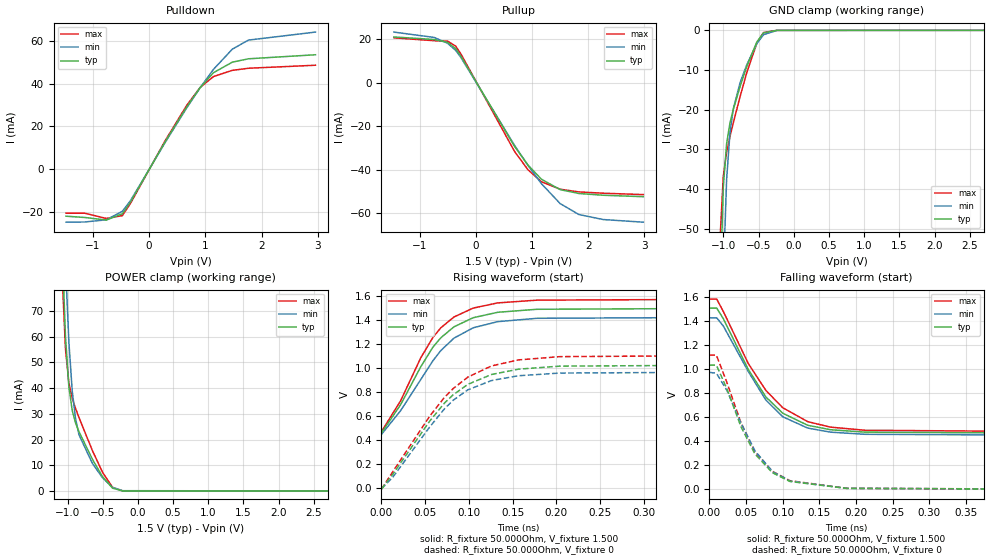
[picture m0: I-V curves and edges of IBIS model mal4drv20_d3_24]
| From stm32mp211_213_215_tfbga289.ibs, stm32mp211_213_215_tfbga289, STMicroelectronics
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[Model] mal4drv20_d3_24
Model_type   I/O
Polarity   Non-Inverting
Enable   Active-High
C_comp   1.836pF   1.830pF   1.844pF
C_comp_pullup   929.639fF   923.197fF   937.397fF
C_comp_pulldown 781.611fF   776.676fF   790.636fF
Vinh = 885.000mV
Vinl = 615.000mV
Vmeas = 750.000mV
Vref = 750.000mV
Rref = 50Ohms
Cref = 0pF
[Model Spec]
Vinh   885.000mV   848.000mV   923.000mV
Vinl   615.000mV   578.000mV   653.000mV
Vmeas   750.000mV   713.000mV   788.000mV
Vref   750.000mV   713.000mV   788.000mV
D_overshoot_ampl_h 0.4 NA   NA
D_overshoot_ampl_l 0.4 NA   NA
D_overshoot_area_l 100.000m NA   NA
D_overshoot_area_h 100.000m NA   NA
[Receiver Thresholds]
Vth = 750.000mV
Vth_min = 713.000mV
Vth_max = 788.000mV
Vinh_ac = 135.000mV
Vinh_dc = 100.000mV
Vinl_ac = -135.000mV
Vinl_dc = -100.000mV
Tslew_ac = 5.000ns
Threshold_sensitivity = 0.5
Reference_supply Pullup_ref
[Temperature Range]   25.000   125.000   -40.000
[Voltage Range]   1.500V   1.425V   1.575V
[GND Clamp Reference]   0.00V   0.00V   0.00V
[C Comp Corner]
| variable   typ   min   max
C_comp 1.844pF   1.836pF   1.830pF
C_comp_pullup 929.639fF   937.397fF   923.197fF
C_comp_pulldown 776.676fF   790.636fF   781.611fF
[Pulldown Reference]   0.00V   0.00V   0.00V
[POWER Clamp Reference]   1.500V   1.425V   1.575V
[Pullup Reference]   1.500V   1.425V   1.575V
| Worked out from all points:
|   slope of the pulldown table from 0 to 0.225 V, typ, clamps not added: 22.1 ohm
|   slope of the pullup table from 0 to 0.225 V, typ, clamps not added: 22.5 ohm
|   GND clamp passes 1 mA (typ) near -0.45 V on its own axis
|   POWER clamp passes 1 mA (typ) near -0.36 V on its own axis
|   rising waveform, R_fixture 50.000Ohm, V_fixture 1.500: 20-80 % time 54ps typ, 57.9ps min, 51.5ps max; typ from 0.461 V to 1.5 V
|   rising waveform, R_fixture 50.000Ohm, V_fixture 0: 20-80 % time 69.1ps typ, 66.6ps min, 71.4ps max; typ from -0.006 V to 1.03 V
|   falling waveform, R_fixture 50.000Ohm, V_fixture 1.500: 20-80 % time 62.2ps typ, 60.1ps min, 67.5ps max; typ from 1.51 V to 0.465 V
|   falling waveform, R_fixture 50.000Ohm, V_fixture 0: 20-80 % time 48.8ps typ, 50.1ps min, 49.4ps max; typ from 1.03 V to 0 V
[GND Clamp]
-1.48V    -1.637A    -1.644A    -1.658A
-1.05V    -67.86mA   -111.2mA   -53.06mA
-1.002V   -39.45mA   -62.21mA   -36.77mA
-954.6mV  -28.48mA   -37.5mA    -30.67mA
-906.8mV  -23.32mA   -25.75mA   -26.73mA
-859.1mV  -19.86mA   -19.72mA   -23.25mA
-763.6mV  -14.17mA   -13.2mA    -16.7mA
-668.2mV  -9.09mA    -8.668mA   -10.65mA
-525mV    -2.932mA   -3.341mA   -3.236mA
-429.5mV  -625.7uA   -1.091mA   -535.7uA
-238.6mV  -2.309uA   -20.7uA    -473nA
2.959V    72.19nA    968.6nA    105nA
[Power Clamp]
-1.459V   654.6mA    675.2mA    655.4mA
-1.077V   94.79mA    129.9mA    83.6mA
-1.03V    59.92mA    88.13mA    55.16mA
-981.8mV  40.46mA    57.96mA    42.01mA
-934.1mV  31.26mA    38.88mA    36.03mA
-886.4mV  26.43mA    28.01mA    32.07mA
-838.6mV  23.06mA    21.89mA    28.58mA
-647.7mV  12.32mA    10.7mA     15.7mA
-504.6mV  5.603mA    5.163mA    7.311mA
-361.4mV  1.062mA    1.366mA    1.412mA
-218.2mV  16.86uA    87.94uA    13.19uA
2.98V     -71.2nA    -1.524uA   -71.42nA
[Pulldown]
-1.48V    -22mA      -24.8mA    -20.6mA
-1.145V   -22.6mA    -24.7mA    -20.6mA
-763.6mV  -23.8mA    -23.7mA    -23.05mA
-477.3mV  -20.88mA   -19.72mA   -21.75mA
-334.1mV  -15.42mA   -14.8mA    -16.09mA
286.4mV   12.91mA    12.56mA    13.39mA
668.2mV   29.09mA    28.64mA    29.82mA
906.8mV   38.09mA    38.07mA    38.2mA
1.145V    45.13mA    46.69mA    43.32mA
1.48V     50.04mA    56.12mA    46.2mA
1.766V    51.61mA    60.36mA    47.19mA
2.959V    53.5mA     64.1mA     48.6mA
[Pullup]
-1.459V   20.9mA     23.14mA    20.5mA
-743.2mV  19.74mA    20.69mA    19.18mA
-504.6mV  18.41mA    18.01mA    18.98mA
-361.4mV  15.58mA    14.78mA    16.73mA
-265.9mV  12mA       11.46mA    13.06mA
688.6mV   -29.34mA   -28.88mA   -31.66mA
927.3mV   -37.9mA    -38.06mA   -40.07mA
1.166V    -44.38mA   -46.42mA   -45.55mA
1.5V      -49.17mA   -55.59mA   -48.97mA
1.834V    -50.94mA   -60.59mA   -50.21mA
2.264V    -51.73mA   -62.88mA   -50.8mA
2.98V     -52.4mA    -64.1mA    -51.44mA
[Ramp]
R_load=50.000Ohm
dV/dt_r   618.870mV/62.500ps  583.738mV/63.000ps  661.260mV/62.500ps
dV/dt_f   618.870mV/56.500ps  583.739mV/56.000ps  661.260mV/59.500ps
[Rising waveform]
R_fixture=50.000Ohm
V_fixture=1.500
V_fixture_min=1.425
V_fixture_max=1.575
0s        461.2mV    448.8mV    471.8mV
22ps      697.2mV    647.1mV    729.7mV
45ps      1.012V     905.9mV    1.086V
59ps      1.176V     1.063V     1.257V
68ps      1.253V     1.147V     1.336V
83ps      1.344V     1.25V      1.426V
105ps     1.42V      1.336V     1.5V
133ps     1.465V     1.387V     1.543V
178ps     1.49V      1.415V     1.566V
469ps     1.5V       1.425V     1.575V
[Rising waveform]
R_fixture=50.000Ohm
V_fixture=0
0s        -6.259mV   -3.866mV   -6.386mV
13ps      118mV      92.93mV    139mV
55ps      557.6mV    508.8mV    598.4mV
72ps      708.9mV    661.2mV    756.2mV
82ps      778.3mV    733.1mV    830mV
99ps      865.9mV    820.4mV    926.4mV
126ps     947.6mV    897.3mV    1.019V
157ps     992mV      937.3mV    1.069V
204ps     1.017V     959.4mV    1.096V
469ps     1.028V     969.6mV    1.108V
[Falling waveform]
R_fixture=50.000Ohm
V_fixture=1.500
V_fixture_min=1.425
V_fixture_max=1.575
0s        1.507V     1.426V     1.582V
10ps      1.507V     1.426V     1.582V
19ps      1.419V     1.358V     1.479V
53ps      996.3mV    980mV      1.046V
77ps      767.4mV    741.6mV    822.1mV
100ps     632.1mV    602.5mV    677.9mV
134ps     531.8mV    508.5mV    562mV
165ps     494.7mV    474.5mV    516.3mV
212ps     474.5mV    456.6mV    490.3mV
479ps     465.4mV    448.9mV    478.4mV
[Falling waveform]
R_fixture=50.000Ohm
V_fixture=0
0s        1.032V     971.6mV    1.116V
9ps       1.032V     965.5mV    1.116V
11ps      1.013V     951.5mV    1.093V
24ps      834.2mV    820.4mV    886.5mV
43ps      521.2mV    551.5mV    553.3mV
62ps      293.7mV    320.4mV    313.5mV
86ps      136.3mV    146.4mV    148.1mV
110ps     63.83mV    68.15mV    70.31mV
187ps     6.519mV    6.582mV    7.409mV
478ps     3.689uV    11.19uV    3.754uV
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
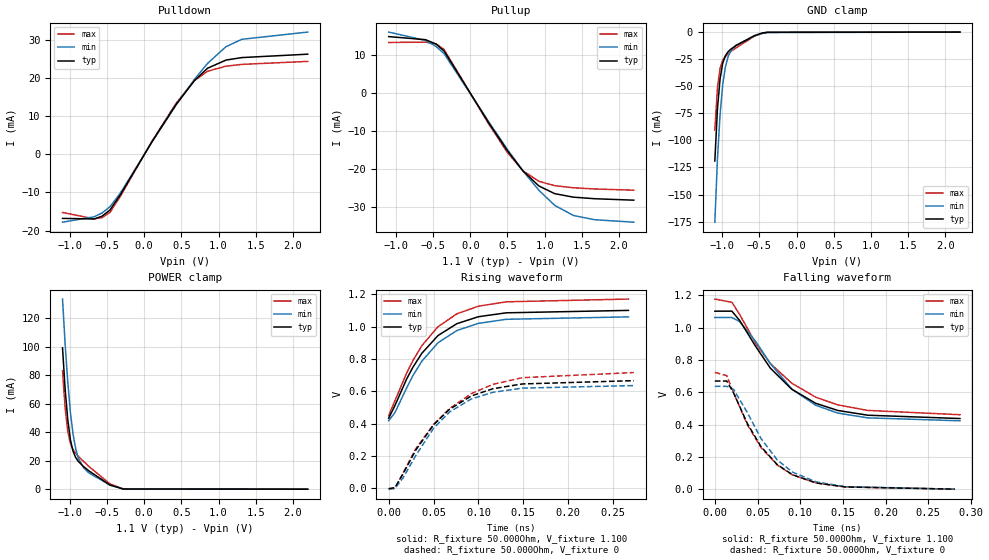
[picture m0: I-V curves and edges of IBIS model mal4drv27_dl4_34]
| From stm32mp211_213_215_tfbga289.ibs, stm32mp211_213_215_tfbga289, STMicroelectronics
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[Model] mal4drv27_dl4_34
Model_type   I/O
Polarity   Non-Inverting
Enable   Active-High
C_comp   1.656pF   1.654pF   1.662pF
C_comp_pullup   832.475fF   825.290fF   839.619fF
C_comp_pulldown 737.556fF   736.745fF   750.731fF
Vinh = 387.000mV
Vinl = 267.000mV
Vmeas = 327.000mV
Vref = 0.00V
Rref = 50Ohms
Cref = 0pF
[Model Spec]
Vinh   387.000mV   375.000mV   408.000mV
Vinl   267.000mV   255.000mV   288.000mV
Vmeas   327.000mV   315.000mV   348.000mV
Vref   0.00V   0.00V   0.00V
D_overshoot_ampl_h 0.3 NA   NA
D_overshoot_ampl_l 0.3 NA   NA
D_overshoot_area_l 100.000m NA   NA
D_overshoot_area_h 100.000m NA   NA
[Receiver Thresholds]
Vth = 327.000mV
Vth_min = 315.000mV
Vth_max = 348.000mV
Vinh_ac = 600.000mV
Vinh_dc = 600.000mV
Vinl_ac = -600.000mV
Vinl_dc = -600.000mV
Tslew_ac = 5.000ns
Threshold_sensitivity = 0.5
Reference_supply Pullup_ref
[Temperature Range]   25.000   125.000   -40.000
[Voltage Range]   1.100V   1.060V   1.170V
[GND Clamp Reference]   0.00V   0.00V   0.00V
[C Comp Corner]
| variable   typ   min   max
C_comp 1.662pF   1.656pF   1.654pF
C_comp_pullup 832.475fF   839.619fF   825.290fF
C_comp_pulldown 736.745fF   750.731fF   737.556fF
[Pulldown Reference]   0.00V   0.00V   0.00V
[POWER Clamp Reference]   1.100V   1.060V   1.170V
[Pullup Reference]   1.100V   1.060V   1.170V
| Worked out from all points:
|   slope of the pulldown table from 0 to 0.165 V, typ, clamps not added: 31.5 ohm
|   slope of the pullup table from 0 to 0.165 V, typ, clamps not added: 31.4 ohm
|   GND clamp passes 1 mA (typ) near -0.47 V on its own axis
|   POWER clamp passes 1 mA (typ) near -0.37 V on its own axis
|   rising waveform, R_fixture 50.000Ohm, V_fixture 1.100: 20-80 % time 49ps typ, 48.4ps min, 50.2ps max; typ from 0.434 V to 1.1 V
|   rising waveform, R_fixture 50.000Ohm, V_fixture 0: 20-80 % time 59ps typ, 54.4ps min, 67.7ps max; typ from -0.002 V to 0.666 V
|   falling waveform, R_fixture 50.000Ohm, V_fixture 1.100: 20-80 % time 65.3ps typ, 62ps min, 71.3ps max; typ from 1.1 V to 0.437 V
|   falling waveform, R_fixture 50.000Ohm, V_fixture 0: 20-80 % time 50.4ps typ, 50.2ps min, 51ps max; typ from 0.669 V to 0 V
[GND Clamp]
-1.099V   -119mA     -175.5mA   -90.46mA
-1.064V   -70.81mA   -117.3mA   -51.1mA
-1.028V   -42.76mA   -75.52mA   -33.21mA
-992.7mV  -28.64mA   -48.36mA   -25.94mA
-957.3mV  -21.83mA   -32.18mA   -22.47mA
-921.8mV  -18.22mA   -22.95mA   -20.16mA
-886.4mV  -15.9mA    -17.64mA   -18.21mA
-815.5mV  -12.5mA    -12.17mA   -14.62mA
-567.3mV  -3.324mA   -3.512mA   -3.774mA
-460.9mV  -879.1uA   -1.269mA   -863.6uA
-390mV    -181.5uA   -432.7uA   -123.2uA
2.198V    31.48nA    451.7nA    3.508nA
[Power Clamp]
-1.098V   99.1mA     133.3mA    83.09mA
-1.063V   70.06mA    101.6mA    56.85mA
-1.027V   48.48mA    74.82mA    40.4mA
-991.8mV  34.54mA    53.74mA    31.95mA
-956.4mV  26.58mA    38.45mA    27.74mA
-920.9mV  22.17mA    28.22mA    25.15mA
-885.5mV  19.46mA    21.74mA    23.1mA
-814.5mV  15.82mA    14.94mA    19.43mA
-743.6mV  12.83mA    11.41mA    15.93mA
-460mV    2.904mA    2.84mA     3.733mA
-282.7mV  117.7uA    274uA      108uA
2.199V    -10.68nA   -391.6nA   -2.283nA
[Pulldown]
-1.099V   -16.8mA    -17.8mA    -15.24mA
-673.6mV  -16.96mA   -16.38mA   -16.92mA
-567.3mV  -16.22mA   -15.38mA   -16.62mA
-460.9mV  -14.6mA    -13.74mA   -15.23mA
-319.1mV  -10.52mA   -10.09mA   -10.94mA
106.4mV   3.403mA    3.314mA    3.527mA
425.4mV   13.01mA    12.87mA    13.33mA
673.6mV   19.33mA    19.65mA    19.36mA
850.9mV   22.6mA     23.87mA    21.82mA
1.099V    24.75mA    28.26mA    23.15mA
1.312V    25.41mA    30.21mA    23.62mA
2.198V    26.3mA     32.1mA     24.41mA
[Pullup]
-1.098V   14.9mA     16.09mA    13.36mA
-601.8mV  14.08mA    13.87mA    13.44mA
-460mV    12.93mA    12.3mA     12.97mA
-353.6mV  11.12mA    10.43mA    11.54mA
249.1mV   -7.854mA   -7.59mA    -8.184mA
497.3mV   -15.13mA   -14.8mA    -15.58mA
710mV     -20.55mA   -20.53mA   -20.5mA
922.7mV   -24.46mA   -25.6mA    -23.24mA
1.135V    -26.48mA   -29.56mA   -24.38mA
1.384V    -27.4mA    -32.21mA   -24.93mA
1.667V    -27.81mA   -33.34mA   -25.24mA
2.199V    -28.2mA    -34mA      -25.57mA
[Ramp]
R_load=50.000Ohm
dV/dt_r   399.330mV/55.000ps  382.229mV/52.000ps  428.760mV/60.000ps
dV/dt_f   399.330mV/59.000ps  382.229mV/57.500ps  428.760mV/62.500ps
[Rising waveform]
R_fixture=50.000Ohm
V_fixture=1.100
V_fixture_min=1.060
V_fixture_max=1.170
0s        433.8mV    418.1mV    448.9mV
7ps       512.6mV    469.2mV    542.5mV
20ps      676.1mV    620.8mV    713.1mV
27ps      749.1mV    697.2mV    790mV
37ps      835.4mV    786.7mV    882.4mV
55ps      944.9mV    900.5mV    999.6mV
76ps      1.018V     975.8mV    1.079V
100ps     1.061V     1.02V      1.126V
131ps     1.085V     1.045V     1.153V
267ps     1.1V       1.06V      1.17V
[Rising waveform]
R_fixture=50.000Ohm
V_fixture=0
0s        -2.303mV   -4.655mV   -1.092mV
7ps       5.401mV    285.6uV    -1.092mV
16ps      90.33mV    64.76mV    94.54mV
30ps      235.7mV    201.7mV    243.6mV
50ps      393.3mV    371.9mV    395.7mV
68ps      490mV      473.2mV    494.2mV
92ps      571.3mV    552.6mV    585.8mV
116ps     615.9mV    593.8mV    642.9mV
149ps     645.6mV    619.7mV    684.4mV
273ps     665.9mV    635.4mV    715.9mV
[Falling waveform]
R_fixture=50.000Ohm
V_fixture=1.100
V_fixture_min=1.060
V_fixture_max=1.170
0s        1.101V     1.062V     1.176V
20ps      1.101V     1.062V     1.156V
29ps      1.044V     1.037V     1.081V
48ps      881.4mV    912.8mV    900.4mV
65ps      748.6mV    776.8mV    776.9mV
90ps      618.4mV    619.9mV    656mV
118ps     531.5mV    519.5mV    569.3mV
144ps     487mV      470.8mV    521.4mV
179ps     457.7mV    441.3mV    487.3mV
287ps     437.1mV    423.1mV    460.7mV
[Falling waveform]
R_fixture=50.000Ohm
V_fixture=0
0s        669mV      636.3mV    722.8mV
14ps      669mV      636.3mV    702.1mV
22ps      595.2mV    617.3mV    595.6mV
38ps      406.8mV    474.2mV    398.7mV
54ps      263.4mV    313.9mV    258.2mV
73ps      152.3mV    181.3mV    149.9mV
91ps      89.06mV    105.6mV    88.22mV
119ps     38.05mV    44.7mV     38.52mV
153ps     13.87mV    15.75mV    14.13mV
281ps     281.4uV    370.9uV    279.5uV
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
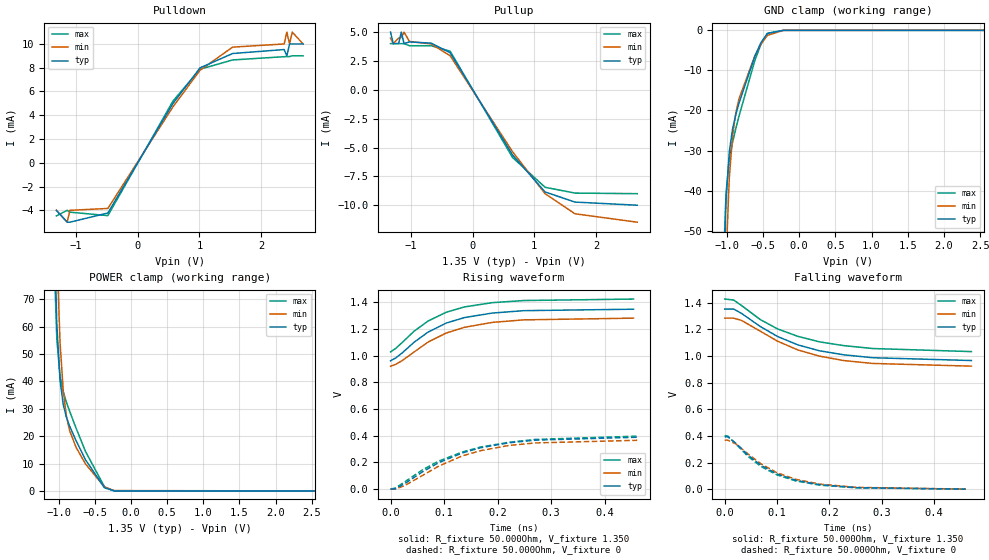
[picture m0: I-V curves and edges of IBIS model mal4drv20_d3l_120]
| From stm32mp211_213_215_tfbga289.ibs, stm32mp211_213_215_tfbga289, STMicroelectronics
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[Model] mal4drv20_d3l_120
Model_type   I/O
Polarity   Non-Inverting
Enable   Active-High
C_comp   1.902pF   1.872pF   1.915pF
C_comp_pullup   928.637fF   913.380fF   944.342fF
C_comp_pulldown   824.069fF   818.585fF   846.427fF
Vinh = 805.000mV
Vinl = 545.000mV
Vmeas = 675.000mV
Vref = 675.000mV
Rref = 50Ohms
Cref = 0pF
[Model Spec]
Vinh   805.000mV   772.000mV   855.000mV
Vinl   545.000mV   512.000mV   595.000mV
Vmeas   675.000mV   642.000mV   725.000mV
Vref   675.000mV   642.000mV   725.000mV
D_overshoot_ampl_h 0.4 NA   NA
D_overshoot_ampl_l 0.4 NA   NA
D_overshoot_area_l 110.000m NA   NA
D_overshoot_area_h 110.000m NA   NA
[Temperature Range]   25.000   125.000   -40.000
[Voltage Range]   1.350V   1.283V   1.425V
[GND Clamp Reference]   0.00V   0.00V   0.00V
[C Comp Corner]
| variable   typ   min   max
C_comp   1.902pF   1.872pF   1.915pF
C_comp_pullup   928.637fF   913.380fF   944.342fF
C_comp_pulldown   824.069fF   818.585fF   846.427fF
[Pulldown Reference]   0.00V   0.00V   0.00V
[POWER Clamp Reference]   1.350V   1.283V   1.425V
[Pullup Reference]   1.350V   1.283V   1.425V
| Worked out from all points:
|   slope of the pulldown table from 0 to 0.203 V, typ, clamps not added: 110 ohm
|   slope of the pullup table from 0 to 0.203 V, typ, clamps not added: 110 ohm
|   GND clamp passes 1 mA (typ) near -0.45 V on its own axis
|   POWER clamp passes 1 mA (typ) near -0.36 V on its own axis
|   rising waveform, R_fixture 50.000Ohm, V_fixture 1.350: 20-80 % time 97.7ps typ, 102ps min, 95ps max; typ from 0.962 V to 1.35 V
|   rising waveform, R_fixture 50.000Ohm, V_fixture 0: 20-80 % time 129ps typ, 125ps min, 136ps max; typ from -0.001 V to 0.389 V
|   falling waveform, R_fixture 50.000Ohm, V_fixture 1.350: 20-80 % time 128ps typ, 126ps min, 133ps max; typ from 1.35 V to 0.965 V
|   falling waveform, R_fixture 50.000Ohm, V_fixture 0: 20-80 % time 95.6ps typ, 100ps min, 93.3ps max; typ from 0.393 V to 0 V
[GND Clamp]
-1.318V   -686mA     -651mA     -676.6mA
-1.054V   -69.51mA   -92.98mA   -61.5mA
-1.011V   -42.32mA   -57.23mA   -40.65mA
-966.7mV  -30.43mA   -37.18mA   -32.46mA
-922.7mV  -24.78mA   -26.66mA   -28.13mA
-878.8mV  -21.23mA   -20.9mA    -24.74mA
-834.8mV  -18.37mA   -17.26mA   -21.6mA
-615.2mV  -6.586mA   -6.461mA   -7.659mA
-527.3mV  -3.034mA   -3.4mA     -3.384mA
-439.4mV  -781.6uA   -1.257mA   -743.1uA
-219.7mV  -1.283uA   -13.11uA   -273nA
2.68V     25.63nA    1.299uA    32.1nA
[Power Clamp]
-1.33V    899mA      850.7mA    889.8mA
-1.067V   105mA      139.9mA    90.42mA
-1.023V   60.65mA    86.8mA     55.41mA
-978.8mV  40.4mA     54.38mA    41.96mA
-934.8mV  31.55mA    36.68mA    36.18mA
-890.9mV  26.93mA    27.34mA    32.42mA
-847mV    23.72mA    22.07mA    29.16mA
-759.1mV  18.45mA    16.02mA    23.04mA
-627.3mV  11.37mA    9.873mA    14.42mA
-363.6mV  1.126mA    1.418mA    1.461mA
-231.8mV  28.01uA    121.4uA    24.12uA
2.668V    -37.81nA   -1.074uA   -20.03nA
[Pulldown]
-1.318V   -4mA       -4mA       -4.473mA
-1.142V   -5mA       -5mA       -4mA
-1.099V   -5mA       -4mA       -4.157mA
-483.3mV  -4.227mA   -3.843mA   -4.447mA
571.2mV   4.994mA    4.709mA    5.192mA
1.011V    7.991mA    7.793mA    7.877mA
1.538V    9.196mA    9.733mA    8.656mA
2.373V    9.53mA     10mA       8.929mA
2.417V    9mA        11mA       8.94mA
2.461V    10mA       10mA       8.94mA
2.505V    10mA       11mA       9mA
2.68V     10mA       10mA       9mA
[Pullup]
-1.33V    5mA        4.475mA    4mA
-1.286V   4mA        4mA        4mA
-1.199V   4mA        4.476mA    4mA
-1.155V   5mA        4.526mA    4mA
-1.111V   4mA        5mA        4mA
-1.023V   4.15mA     4.184mA    3.817mA
-671.2mV  4.04mA     3.973mA    3.819mA
-363.6mV  3.209mA    2.95mA     3.345mA
647mV     -5.641mA   -5.364mA   -5.862mA
1.174V    -8.848mA   -8.997mA   -8.445mA
1.658V    -9.727mA   -10.74mA   -8.948mA
2.668V    -10mA      -11.47mA   -9mA
[Ramp]
R_load=50.000Ohm
dV/dt_r   233.700mV/115.500ps  218.997mV/116.000ps  239.400mV/118.500ps
dV/dt_f   233.700mV/113.500ps  218.997mV/115.500ps  239.400mV/116.000ps
[Rising waveform]
R_fixture=50.000Ohm
V_fixture=1.350
V_fixture_min=1.283
V_fixture_max=1.425
0s        962mV      921mV      1.028V
10ps      984mV      936mV      1.056V
22ps      1.022V     964mV      1.1V
44ps      1.101V     1.028V     1.184V
70ps      1.177V     1.102V     1.26V
104ps     1.245V     1.17V      1.326V
138ps     1.286V     1.213V     1.366V
190ps     1.32V      1.25V      1.398V
249ps     1.338V     1.269V     1.414V
454ps     1.349V     1.282V     1.425V
[Rising waveform]
R_fixture=50.000Ohm
V_fixture=0
0s        -554.7uV   -439.5uV   -167uV
9ps       2.492mV    -439.5uV   8.073mV
27ps      42.03mV    26.98mV    55.29mV
60ps      130mV      103mV      145mV
90ps      198mV      172mV      210mV
134ps     271mV      249mV      278mV
168ps     310mV      288mV      315mV
221ps     347mV      327mV      351mV
270ps     367mV      346mV      372mV
461ps     389mV      366mV      397mV
[Falling waveform]
R_fixture=50.000Ohm
V_fixture=1.350
V_fixture_min=1.283
V_fixture_max=1.425
0s        1.351V     1.283V     1.426V
17ps      1.351V     1.283V     1.419V
32ps      1.319V     1.266V     1.378V
68ps      1.22V      1.185V     1.272V
101ps     1.145V     1.11V      1.202V
140ps     1.082V     1.044V     1.146V
181ps     1.038V     998mV      1.105V
227ps     1.008V     965mV      1.077V
283ps     986mV      943mV      1.055V
471ps     965mV      923mV      1.032V
[Falling waveform]
R_fixture=50.000Ohm
V_fixture=0
0s        393mV      368mV      402mV
6ps       393mV      368mV      399mV
22ps      342mV      338mV      336mV
45ps      254mV      263mV      244mV
69ps      180mV      191mV      171mV
100ps     114mV      123mV      107mV
136ps     66.75mV    73.86mV    61.6mV
181ps     34mV       38.49mV    30.92mV
251ps     11.8mV     13.96mV    10.45mV
460ps     479.6uV    683.7uV    350.3uV
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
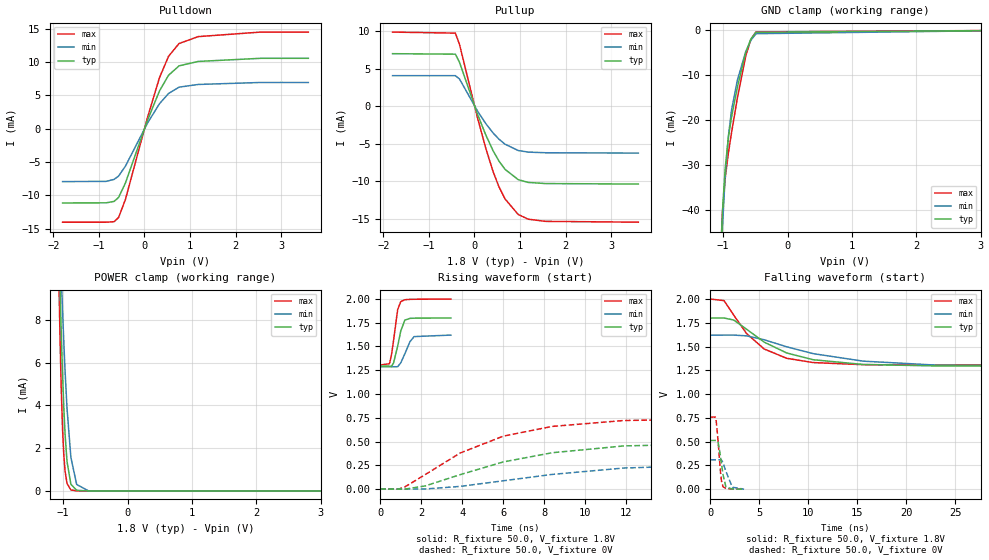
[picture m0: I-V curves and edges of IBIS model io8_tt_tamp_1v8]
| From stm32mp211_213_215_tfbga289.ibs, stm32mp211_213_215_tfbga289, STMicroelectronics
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[Model]   io8_tt_tamp_1v8
Model_type I/O
Polarity   Non-Inverting
Enable   Active-Low
| CAP_THRESHOLD on pad IOTT is "UDTCAPC" :
| Rising=30.0% of vddiov33m   Falling=70.0% of vddiov33m
| C_comp min and max val. don't necessarily correlate with the min and max pvt
| but are the smallest and greatest pad capacitance found.
| var   typ   min   max
C_comp   1.43337pF  1.39420pF  1.45608pF
|C_comp_pullup   766.63000fF  745.57000fF  782.38000fF
|C_comp_pulldown   666.73555fF  648.63000fF  673.69555fF
Vinl = 486.0mV
Vinh = 1.4V
Vmeas = 900.0mV   | Reference voltage for timing measurements
Cref  = 50.0pF   | Timing specification test load capacitance value
Rref  = 100.0MOhm   | Timing specification test load resistance value
Vref  = 900.0mV   | Timing specification test load voltage
[Model Spec]
| TIME_THRESHOLD on pin ZIV08SW is "CMOS" :
| Rising=50.0% of vddv08sw   Falling=50.0% of vddv08sw
Vinl 1.07470V 960.70000mV 1.21270V
Vinh 1.54130V 1.38830V 1.70930V
| variable   typ   min   max
[Temperature Range] 25.0 125.0 -40.0
| variable   typ   min   max
[Voltage Range] 1.8V 1.62V 2.0V
| variable   typ   min   max
[POWER Clamp Reference] 1.8V 1.62V 2.0V
| variable   typ   min   max
[GND Clamp Reference] 0V 0V 0V
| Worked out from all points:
|   slope of the pulldown table from 0 to 0.27 V, typ, clamps not added: 56.7 ohm
|   slope of the pullup table from 0 to 0.27 V, typ, clamps not added: 64.9 ohm
|   GND clamp passes 1 mA (typ) near -0.53 V on its own axis
|   POWER clamp passes 1 mA (typ) near -0.93 V on its own axis
|   rising waveform, R_fixture 50.0, V_fixture 1.8V: 20-80 % time 302ps typ, 396ps min, 257ps max; typ from 1.29 V to 1.8 V
|   falling waveform, R_fixture 50.0, V_fixture 1.8V: 20-80 % time 5.52ns typ, 8.94ns min, 3.81ns max; typ from 1.8 V to 1.29 V
|   rising waveform, R_fixture 50.0, V_fixture 0V: 20-80 % time 6.21ns typ, 9.11ns min, 4.77ns max; typ from 0 V to 0.513 V
|   falling waveform, R_fixture 50.0, V_fixture 0V: 20-80 % time 424ps typ, 592ps min, 351ps max; typ from 0.513 V to 0 V
[POWER Clamp]
-1.8V     154.4mA    107.2mA    224.4mA
-1.07V    12.25mA    13.82mA    10.53mA
-1.05V    9.71mA     11.92mA    7.356mA
-1.03V    7.448mA    10.14mA    4.814mA
-1.01V    5.5mA      8.481mA    2.941mA
-990mV    3.897mA    6.96mA     1.687mA
-970mV    2.647mA    5.594mA    920uA
-940mV    1.378mA    3.862mA    349.3uA
-880mV    312.8uA    1.571mA    46.29uA
-790mV    28.91uA    302.9uA    2.224uA
-610mV    227.4nA    7.337uA    51.98nA
3.6V      0A         0A         0A
[GND Clamp]
-1.8V     -1.26A     -1.243A    -1.27A
-1.05V    -54.95mA   -59.03mA   -53.77mA
-1.04V    -50.56mA   -54.58mA   -49.57mA
-1.01V    -40.14mA   -43.55mA   -40.35mA
-970mV    -30.92mA   -32.83mA   -33.09mA
-920mV    -23.94mA   -23.73mA   -27.4mA
-870mV    -19.28mA   -17.79mA   -22.75mA
-780mV    -12.68mA   -11.12mA   -15.12mA
-650mV    -4.981mA   -4.775mA   -5.752mA
-570mV    -1.933mA   -2.222mA   -2.038mA
-490mV    -432.5uA   -742.2uA   -346.4uA
3.6V      85.28nA    4.118uA    46.49nA
| variable   typ   min   max
[Pullup Reference] 1.8V 1.62V 2.0V
| variable   typ   min   max
[Pulldown Reference] 0V 0V 0V
[Pullup]
-1.8V     6.977mA    4.047mA    9.855mA
-420mV    6.911mA    4.047mA    9.716mA
-330mV    5.842mA    3.61mA     8.232mA
70mV      -1.149mA   -704.5uA   -1.66mA
250mV     -3.883mA   -2.354mA   -5.669mA
410mV     -5.971mA   -3.598mA   -8.759mA
540mV     -7.355mA   -4.429mA   -10.8mA
670mV     -8.429mA   -5.083mA   -12.37mA
960mV     -9.808mA   -5.925mA   -14.45mA
1.18V     -10.18mA   -6.139mA   -15.08mA
1.56V     -10.33mA   -6.226mA   -15.37mA
3.6V      -10.4mA    -6.27mA    -15.48mA
[Pulldown]
-1.8V     -11.16mA   -7.952mA   -14.05mA
-840mV    -11.14mA   -7.917mA   -14.05mA
-670mV    -10.93mA   -7.621mA   -13.98mA
-570mV    -10.34mA   -7.128mA   -13.35mA
-420mV    -8.184mA   -5.644mA   -10.66mA
70mV      1.323mA    886.5uA    1.768mA
330mV     5.679mA    3.752mA    7.67mA
530mV     8.037mA    5.296mA    10.89mA
760mV     9.437mA    6.239mA    12.79mA
1.18V     10.1mA     6.642mA    13.83mA
2.55V     10.57mA    6.941mA    14.51mA
3.6V      10.57mA    6.941mA    14.51mA
[Ramp]
dV/dt_r 307.6074mV/6.20448ns 185.63692mV/8.92682ns 455.16958mV/4.7748ns
dV/dt_f 304.11761mV/5.516ns 199.74041mV/8.88907ns 416.77708mV/3.81105ns
R_load = 50.0
| Removed startup time: 0s 0s 0s  .
| Removed end time: 3.45ns.
[Rising Waveform]
R_fixture   = 50.0
V_fixture   = 1.8V
V_fixture_min = 1.62V
V_fixture_max = 2.0V
0s        1.293V     1.287V     1.305V
450ps     1.293V     1.287V     1.319V
550ps     1.292V     1.287V     1.415V
650ps     1.328V     1.287V     1.565V
850ps     1.505V     1.287V     1.889V
1ns       1.663V     1.328V     1.972V
1.2ns     1.777V     1.423V     1.992V
1.45ns    1.796V     1.551V     1.996V
1.65ns    1.798V     1.604V     1.997V
3.45ns    1.8V       1.62V      1.999V
| Removed startup time: 0s 0s 0s  .
| Removed end time: 69.9ns.
[Falling Waveform]
R_fixture   = 50.0
V_fixture   = 1.8V
V_fixture_min = 1.62V
V_fixture_max = 2.0V
0s        1.8V       1.62V      2V
1.4ns     1.801V     1.621V     1.984V
2.4ns     1.779V     1.621V     1.83V
3.7ns     1.683V     1.613V     1.638V
5.5ns     1.547V     1.572V     1.475V
7.8ns     1.433V     1.498V     1.377V
10.5ns    1.362V     1.426V     1.332V
15.6ns    1.312V     1.347V     1.31V
23.3ns    1.296V     1.304V     1.306V
69.9ns    1.293V     1.287V     1.305V
| Removed startup time: 0s 0s 0s  .
| Removed end time: 69.9ns.
[Rising Waveform]
R_fixture   = 50.0
V_fixture   = 0V
V_fixture_min = 0V
V_fixture_max = 0V
0s        349.5nV    4.949uV    499nV
900ps     -1.26mV    -599uV     -369uV
1.2ns     -787.7uV   -842.3uV   22.54mV
2.2ns     33.14mV    1.018mV    152.9mV
3.9ns     151.4mV    27.73mV    379.1mV
6ns       285mV      86.74mV    556.1mV
8.4ns     382.3mV    154.1mV    659.1mV
11.9ns    453.9mV    221.4mV    721.3mV
23.3ns    507.4mV    294.2mV    756.8mV
69.9ns    512.7mV    309.4mV    758.6mV
| Removed startup time: 0s 0s 0s  .
| Removed end time: 3.45ns.
[Falling Waveform]
R_fixture   = 50.0
V_fixture   = 0V
V_fixture_min = 0V
V_fixture_max = 0V
0s        512.7mV    309.4mV    758.6mV
500ps     512.7mV    309.4mV    759.7mV
600ps     512.6mV    309.4mV    721.9mV
800ps     493.2mV    309.4mV    504.4mV
1.05ns    342.9mV    310mV      171.2mV
1.15ns    264.7mV    305.4mV    84.25mV
1.3ns     151.8mV    277.3mV    27.15mV
1.6ns     23.41mV    187.4mV    6.871mV
2.25ns    1.286mV    21.04mV    1.828mV
3.45ns    422.1uV    459.6uV    545.8uV
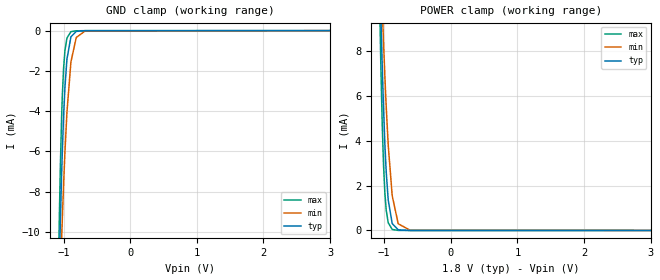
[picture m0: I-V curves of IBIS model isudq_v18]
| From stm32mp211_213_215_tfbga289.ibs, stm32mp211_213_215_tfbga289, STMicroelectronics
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[Model]   isudq_v18
Model_type Input
Polarity   Non-Inverting
Enable   Active-Low
| CAP_THRESHOLD on pad IOV18M is "UDTCAPC" :
| Rising=30.0% of vddiov18m   Falling=70.0% of vddiov18m
| C_comp min and max val. don't necessarily correlate with the min and max pvt
| but are the smallest and greatest pad capacitance found.
| var   typ   min   max
C_comp   1.09083pF  965.56055fF  1.46892pF
|C_comp_pullup   716.60000fF  596.11500fF  902.71500fF
|C_comp_pulldown   374.22769fF  369.44555fF  566.20500fF
Vinl = 810.0mV
Vinh = 1.0V
[Model Spec]
| TIME_THRESHOLD on pin ZIV08M is "CMOS" :
| Rising=50.0% of vddv08m   Falling=50.0% of vddv08m
Vinl 991.70000mV 887.70000mV 1.11970V
Vinh 1.28430V 1.14430V 1.44130V
| variable   typ   min   max
[Temperature Range] 25.0 125.0 -40.0
| variable   typ   min   max
[Voltage Range] 1.8V 1.62V 2.0V
| variable   typ   min   max
[POWER Clamp Reference] 1.8V 1.62V 2.0V
| variable   typ   min   max
[GND Clamp Reference] 0V 0V 0V
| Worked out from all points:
|   GND clamp passes 1 mA (typ) near -0.94 V on its own axis
|   POWER clamp passes 1 mA (typ) near -0.93 V on its own axis
[POWER Clamp]
-1.8V     152.1mA    105.6mA    221.1mA
-1.07V    12.07mA    13.62mA    10.38mA
-1.05V    9.569mA    11.75mA    7.248mA
-1.03V    7.339mA    9.994mA    4.743mA
-1.01V    5.42mA     8.359mA    2.898mA
-990mV    3.841mA    6.86mA     1.662mA
-970mV    2.609mA    5.514mA    906.4uA
-940mV    1.358mA    3.807mA    344uA
-880mV    308.3uA    1.549mA    45.49uA
-790mV    28.48uA    299.7uA    2.1uA
-610mV    225.8nA    8.224uA    4.204nA
3.6V      0A         0A         0A
[GND Clamp]
-1.8V     -182.8mA   -127.9mA   -264.2mA
-1.07V    -12.53mA   -14.65mA   -10.34mA
-1.05V    -9.669mA   -12.45mA   -6.916mA
-1.03V    -7.182mA   -10.39mA   -4.31mA
-1.02V    -6.092mA   -9.426mA   -3.312mA
-1V       -4.24mA    -7.635mA   -1.866mA
-980mV    -2.822mA   -6.045mA   -1mA
-950mV    -1.424mA   -4.065mA   -373.3uA
-890mV    -308.8uA   -1.558mA   -54.59uA
-810mV    -40.51uA   -342.8uA   -10.79uA
-680mV    -5.352uA   -27.64uA   -4.999uA
3.6V      13.11nA    276.8nA    16.27nA
